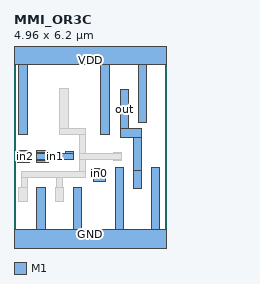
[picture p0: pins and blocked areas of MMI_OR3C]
MACRO MMI_OR3C
	CLASS CORE ;
	FOREIGN MMI_OR3C 0 0 ;
	SIZE 4.96 BY 6.2 ;
	SYMMETRY X Y ;
	SITE CORE1 ;
	PIN out
		DIRECTION output ;
		USE SIGNAL ;
		PORT
			LAYER M1 ;
			RECT 3.465 3.69 3.745 4.975 ;
			LAYER M1 ;
			RECT 3.465 3.405 4.175 3.69 ;
			LAYER M1 ;
			RECT 3.89 2.34 4.175 3.405 ;
			LAYER M1 ;
			RECT 3.89 1.73 4.17 2.34 ;
		END
		AntennaDiffArea 1.0395 ;
	END out
	PIN in1
		DIRECTION input ;
		USE SIGNAL ;
		PORT
			LAYER M1 ;
			RECT 0.74 2.93 1.12 2.98 ;
			LAYER M1 ;
			RECT 0.725 2.885 1.12 2.93 ;
			LAYER M1 ;
			RECT 1.665 2.885 1.945 2.96 ;
			LAYER M1 ;
			RECT 0.725 2.695 1.945 2.885 ;
			LAYER M1 ;
			RECT 0.725 2.65 1.12 2.695 ;
			LAYER M1 ;
			RECT 1.665 2.68 1.945 2.695 ;
			LAYER M1 ;
			RECT 0.74 2.6 1.12 2.65 ;
		END
		AntennaGateArea 0.546 ;
	END in1
	PIN GND
		DIRECTION inout ;
		USE GROUND ;
		PORT
			LAYER M1 ;
			RECT 0.75 0.42 1.03 1.78 ;
			LAYER M1 ;
			RECT 1.93 0.42 2.21 1.78 ;
			LAYER M1 ;
			RECT 3.3 0.42 3.58 2.43 ;
			LAYER M1 ;
			RECT 4.48 0.42 4.76 2.43 ;
			LAYER M1 ;
			RECT 0 -0.42 4.96 0.42 ;
		END
	END GND
	PIN in2
		DIRECTION input ;
		USE SIGNAL ;
		PORT
			LAYER M1 ;
			RECT 0.12 2.6 0.5 2.98 ;
		END
		AntennaGateArea 0.546 ;
	END in2
	PIN VDD
		DIRECTION inout ;
		USE POWER ;
		PORT
			LAYER M1 ;
			RECT 0 5.78 4.96 6.62 ;
			LAYER M1 ;
			RECT 0.16 3.505 0.44 5.78 ;
			LAYER M1 ;
			RECT 2.82 3.505 3.1 5.78 ;
			LAYER M1 ;
			RECT 4.055 3.915 4.335 5.78 ;
		END
	END VDD
	PIN in0
		DIRECTION input ;
		USE SIGNAL ;
		PORT
			LAYER M1 ;
			RECT 2.54 2.36 2.82 2.385 ;
			LAYER M1 ;
			RECT 2.54 2.105 2.98 2.36 ;
			LAYER M1 ;
			RECT 2.6 1.98 2.98 2.105 ;
		END
		AntennaGateArea 0.546 ;
	END in0
	OBS
		LAYER M1 ;
		RECT 1.49 3.695 1.77 4.995 ;
		LAYER M1 ;
		RECT 1.49 3.505 2.335 3.695 ;
		LAYER M1 ;
		RECT 2.145 2.885 2.335 3.505 ;
		LAYER M1 ;
		RECT 3.24 2.885 3.52 2.93 ;
		LAYER M1 ;
		RECT 2.145 2.695 3.52 2.885 ;
		LAYER M1 ;
		RECT 2.145 2.31 2.335 2.695 ;
		LAYER M1 ;
		RECT 3.24 2.65 3.52 2.695 ;
		LAYER M1 ;
		RECT 0.25 2.115 2.335 2.31 ;
		LAYER M1 ;
		RECT 0.25 1.78 0.44 2.115 ;
		LAYER M1 ;
		RECT 1.385 1.78 1.575 2.115 ;
		LAYER M1 ;
		RECT 0.16 1.33 0.44 1.78 ;
		LAYER M1 ;
		RECT 1.34 1.33 1.62 1.78 ;
	END
END MMI_OR3C
